VERSION 5.7 ;
  NOWIREEXTENSIONATPIN ON ;
  DIVIDERCHAR "/" ;
  BUSBITCHARS "[]" ;
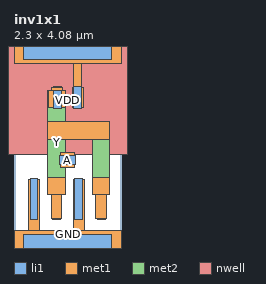
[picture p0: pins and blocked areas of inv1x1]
MACRO inv1x1
  CLASS BLOCK ;
  FOREIGN inv1x1 ;
  ORIGIN 0.000 0.000 ;
  SIZE 2.300 BY 4.080 ;
  PIN A
    ANTENNAGATEAREA 0.441000 ;
    PORT
      LAYER li1 ;
        RECT 0.985 1.660 1.315 1.850 ;
      LAYER met1 ;
        RECT 1.000 1.600 1.300 1.920 ;
    END
  END A
  PIN Y
    ANTENNADIFFAREA 0.659400 ;
    PORT
      LAYER li1 ;
        RECT 0.845 2.870 1.015 3.330 ;
        RECT 0.825 0.490 0.995 1.370 ;
        RECT 1.785 0.490 1.955 1.370 ;
      LAYER met1 ;
        RECT 0.815 3.260 1.045 3.310 ;
        RECT 0.740 2.880 1.100 3.260 ;
        RECT 0.720 2.210 2.060 2.590 ;
        RECT 0.720 1.010 1.100 1.390 ;
        RECT 1.680 1.010 2.060 1.390 ;
        RECT 0.795 0.510 1.025 1.010 ;
        RECT 1.755 0.510 1.985 1.010 ;
      LAYER met2 ;
        RECT 0.720 1.010 1.110 3.260 ;
        RECT 1.680 1.010 2.060 2.590 ;
    END
  END Y
  PIN VDD
    ANTENNADIFFAREA 0.684400 ;
    PORT
      LAYER nwell ;
        RECT -0.230 1.870 2.530 4.410 ;
      LAYER li1 ;
        RECT 0.210 3.915 2.090 4.245 ;
        RECT 1.285 2.870 1.455 3.330 ;
      LAYER met1 ;
        RECT 0.000 3.840 2.300 4.320 ;
        RECT 1.285 3.310 1.455 3.840 ;
        RECT 1.255 2.890 1.485 3.310 ;
    END
  END VDD
  PIN GND
    ANTENNADIFFAREA 1.100200 ;
    PORT
      LAYER li1 ;
        RECT 0.345 0.490 0.515 1.370 ;
        RECT 1.305 0.490 1.475 1.370 ;
        RECT 0.210 -0.165 2.090 0.165 ;
      LAYER met1 ;
        RECT 0.315 0.240 0.545 1.350 ;
        RECT 1.275 0.240 1.505 1.350 ;
        RECT 0.000 -0.240 2.300 0.240 ;
    END
  END GND
END inv1x1
END LIBRARY

